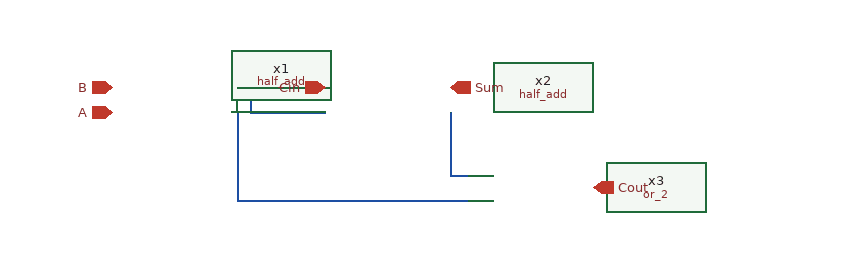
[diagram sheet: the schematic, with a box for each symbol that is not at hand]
v {xschem version=3.4.8RC file_version=1.3}
G {}
K {}
V {}
S {}
F {}
E {}
P 4 1 240 -220 {}
N 150 -240 160 -240 {lab=#net1}
N 160 -240 160 -220 {lab=#net1}
N 160 -220 220 -220 {lab=#net1}
N 150 -220 150 -200 {lab=#net2}
N 150 -200 150 -170 {lab=#net2}
N 150 -170 150 -150 {lab=#net2}
N 150 -150 330 -150 {lab=#net2}
N 330 -150 335 -150 {lab=#net2}
N 320 -220 320 -170 {lab=#net3}
N 320 -170 335 -170 {lab=#net3}
C {title.sym} 160 -50 0 0 {name=l5 author="Stefan Schippers"}
C {/home/suraj/projects/CMOS/HALF_ADDER/schematic/half_add.sym} 200 -230 0 0 {name=x1}
C {/home/suraj/projects/CMOS/HALF_ADDER/schematic/half_add.sym} 370 -230 0 0 {name=x2}
C {ipin.sym} 50 -240 0 0 {name=p1 lab=B}
C {ipin.sym} 50 -220 0 0 {name=p2 lab=A}
C {ipin.sym} 220 -240 0 0 {name=p3 lab=Cin}
C {/home/suraj/projects/CMOS/Mylib/or_2.sym} 485 -160 0 0 {name=x3}
C {opin.sym} 320 -240 0 0 {name=p4 lab=Sum}
C {opin.sym} 435 -160 0 0 {name=p5 lab=Cout}
